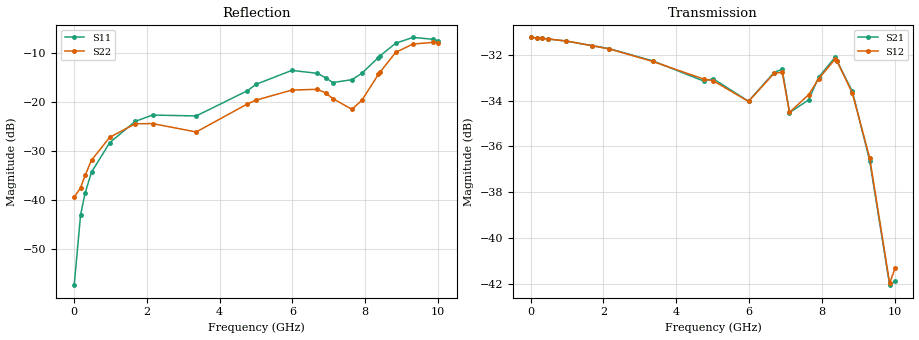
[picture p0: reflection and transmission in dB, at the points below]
! Device ID: PE43705
! Serial: 1
! Insertion: A
! Impedance: 50 ohm
! Temp: 25C
! VDD: 3.400V
! Attenuation Step: 30.25dB
#  Hz  S  RI  R  50
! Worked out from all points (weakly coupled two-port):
!   401 points, 10 MHz to 10.01 GHz, reference 50 ohm
!   highest |S21| = -31.25 dB at 10 MHz (marker M1); lowest = -42.0 dB at 9.86 GHz (marker M2)
!   lowest |S11| = -57.3 dB at 10 MHz (marker M3), VSWR 1.00, Z = 49.9 + j0.0428 ohm
!   |S11| at or under -10 dB: start of sweep to 8.494 GHz
!   |S22| runs from -39.6 to -7.8 dB; largest |S21 - S12| = 0.00058
!   S11 on the Smith chart (normalised r, x): 10 MHz: 1.00, +0.00; 4.76 GHz: 0.80, +0.12; 8.41 GHz: 0.80, +0.52; 9.31 GHz: 0.52, +0.55; 10.01 GHz: 0.47, +0.33
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1e7  -0.00129 0.000429  0.0274 -0.000117  0.0274 -8.21e-05  -0.0107 0.000569
1.85e8  -0.00175 0.00685  0.0273 -0.00122  0.0273 -0.00121  -0.0102 0.00856
3.1e8  -0.00368 0.0112  0.0272 -0.00201  0.0272 -0.00199  -0.0116 0.0136
4.85e8  -0.00836 0.0173  0.027 -0.00315  0.027 -0.00312  -0.0152 0.0204
9.85e8  -0.0309 0.0228  0.0262 -0.00607  0.0262 -0.00612  -0.0327 0.0288
1.685e9  -0.0624 0.0103  0.0244 -0.00981  0.0244 -0.00976  -0.0553 0.0227
2.16e9  -0.0732 -0.00428  0.0229 -0.0121  0.0228 -0.0122  -0.0586 0.0132
3.36e9  -0.0718 -0.00314  0.0179 -0.0165  0.0179 -0.0164  -0.0467 0.0159
4.76e9  -0.1057 0.0749  0.0125 -0.0181  0.0126 -0.0183  -0.0781 0.0542
5.01e9  -0.1214 0.0901  0.0121 -0.0187  0.012 -0.0185  -0.0865 0.0582
5.985e9  -0.1751 0.1144  0.00778 -0.0183  0.00796 -0.0182  -0.1149 0.0645
6.685e9  -0.1663 0.1018  0.00724 -0.0218  0.0072 -0.0217  -0.1237 0.0521
6.91e9  -0.1471 0.0968  0.00413 -0.023  0.00382 -0.0227  -0.1134 0.0492
7.11e9  -0.1315 0.0863  0.00265 -0.0186  0.00278 -0.0186  -0.0954 0.0505
7.635e9  -0.0824 0.1465  0.00405 -0.0196  0.00423 -0.0201  -0.0497 0.0676
7.91e9  -0.0477 0.1898  0.0032 -0.0222  0.00338 -0.022  -0.037 0.0974
8.36e9  -0.0224 0.2819  -0.00382 -0.0245  -0.00352 -0.0243  -0.0363 0.1864
8.41e9  -0.0253 0.2939  -0.00485 -0.0239  -0.00472 -0.0239  -0.0395 0.1973
8.835e9  -0.069 0.389  -0.00973 -0.0185  -0.00933 -0.0185  -0.0976 0.3037
9.31e9  -0.1617 0.4236  -0.00914 -0.0116  -0.00937 -0.0117  -0.203 0.3308
9.86e9  -0.2765 0.334  -0.0029 -0.00735  -0.00272 -0.0075  -0.3358 0.2227
1.001e10  -0.2997 0.2897  -0.00022 -0.00806  -0.000174 -0.00861  -0.3674 0.1632
